###############################################################
#  Generated by:      Cadence Innovus 22.16-s082_1
#  OS:                Linux x86_64(Host ID localhost.localdomain)
#  Generated on:      Sat Aug  8 01:09:43 2026
#  Design:            CNN_1D_Core_USE_ASIC_SRAM1
#  Command:           write_lef_abstract -extractBlockObs -cutObsMinSpacing -specifyTopLayer metal10 -5.8 -extractBlockPGPinLayers {metal9 metal10} /home/hients/my_design/CNN_300_cp3/output/06_route_opt/CNN_1D_Core_USE_ASIC_SRAM1.lef
###############################################################

VERSION 5.8 ;

BUSBITCHARS "[]" ;
DIVIDERCHAR "/" ;

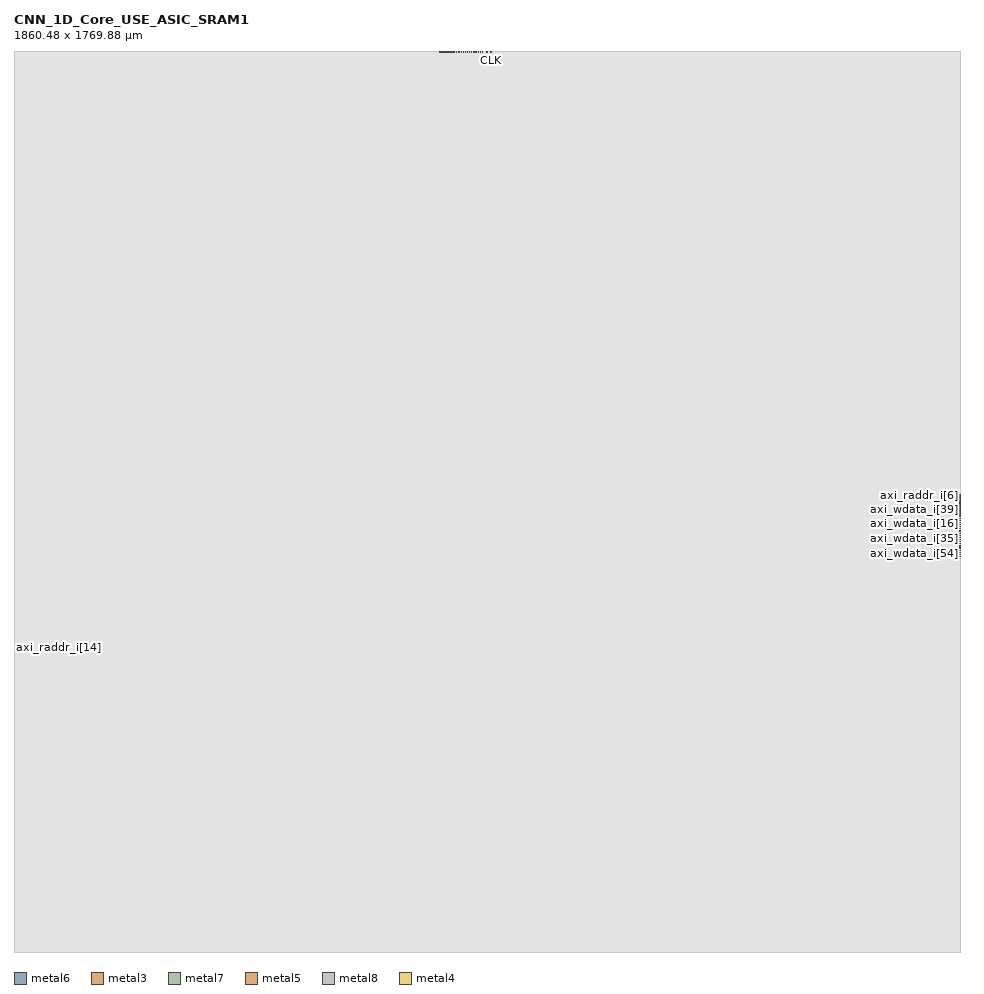
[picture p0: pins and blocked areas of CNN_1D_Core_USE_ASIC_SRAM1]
MACRO CNN_1D_Core_USE_ASIC_SRAM1
  CLASS BLOCK ;
  SIZE 1860.480000 BY 1769.880000 ;
  FOREIGN CNN_1D_Core_USE_ASIC_SRAM1 0.000000 0.000000 ;
  ORIGIN 0 0 ;
  SYMMETRY X Y R90 ;
  PIN CLK
    DIRECTION INPUT ;
    USE SIGNAL ;
    PORT
      LAYER metal6 ;
        RECT 937.990000 1769.740000 938.130000 1769.880000 ;
    END
  END CLK
  PIN RST
    DIRECTION INPUT ;
    USE SIGNAL ;
    PORT
      LAYER metal6 ;
        RECT 930.150000 1769.740000 930.290000 1769.880000 ;
    END
  END RST
  PIN axi_waddr_i[14]
    DIRECTION INPUT ;
    USE SIGNAL ;
    PORT
      LAYER metal3 ;
        RECT 1860.410000 896.245000 1860.480000 896.315000 ;
    END
  END axi_waddr_i[14]
  PIN axi_waddr_i[13]
    DIRECTION INPUT ;
    USE SIGNAL ;
    PORT
      LAYER metal7 ;
        RECT 1860.080000 882.360000 1860.480000 882.760000 ;
    END
  END axi_waddr_i[13]
  PIN axi_waddr_i[12]
    DIRECTION INPUT ;
    USE SIGNAL ;
    PORT
      LAYER metal5 ;
        RECT 1860.340000 893.970000 1860.480000 894.110000 ;
    END
  END axi_waddr_i[12]
  PIN axi_waddr_i[11]
    DIRECTION INPUT ;
    USE SIGNAL ;
    PORT
      LAYER metal3 ;
        RECT 1860.410000 896.945000 1860.480000 897.015000 ;
    END
  END axi_waddr_i[11]
  PIN axi_waddr_i[10]
    DIRECTION INPUT ;
    USE SIGNAL ;
    PORT
      LAYER metal7 ;
        RECT 1860.080000 886.560000 1860.480000 886.960000 ;
    END
  END axi_waddr_i[10]
  PIN axi_waddr_i[9]
    DIRECTION INPUT ;
    USE SIGNAL ;
    PORT
      LAYER metal3 ;
        RECT 1860.410000 894.145000 1860.480000 894.215000 ;
    END
  END axi_waddr_i[9]
  PIN axi_waddr_i[8]
    DIRECTION INPUT ;
    USE SIGNAL ;
    PORT
      LAYER metal7 ;
        RECT 1860.080000 869.760000 1860.480000 870.160000 ;
    END
  END axi_waddr_i[8]
  PIN axi_waddr_i[7]
    DIRECTION INPUT ;
    USE SIGNAL ;
    PORT
      LAYER metal5 ;
        RECT 1860.340000 889.770000 1860.480000 889.910000 ;
    END
  END axi_waddr_i[7]
  PIN axi_waddr_i[6]
    DIRECTION INPUT ;
    USE SIGNAL ;
    PORT
      LAYER metal3 ;
        RECT 1860.410000 894.845000 1860.480000 894.915000 ;
    END
  END axi_waddr_i[6]
  PIN axi_waddr_i[5]
    DIRECTION INPUT ;
    USE SIGNAL ;
    PORT
      LAYER metal7 ;
        RECT 1860.080000 873.960000 1860.480000 874.360000 ;
    END
  END axi_waddr_i[5]
  PIN axi_waddr_i[4]
    DIRECTION INPUT ;
    USE SIGNAL ;
    PORT
      LAYER metal5 ;
        RECT 1860.340000 891.170000 1860.480000 891.310000 ;
    END
  END axi_waddr_i[4]
  PIN axi_waddr_i[3]
    DIRECTION INPUT ;
    USE SIGNAL ;
    PORT
      LAYER metal3 ;
        RECT 1860.410000 895.545000 1860.480000 895.615000 ;
    END
  END axi_waddr_i[3]
  PIN axi_waddr_i[2]
    DIRECTION INPUT ;
    USE SIGNAL ;
    PORT
      LAYER metal7 ;
        RECT 1860.080000 878.160000 1860.480000 878.560000 ;
    END
  END axi_waddr_i[2]
  PIN axi_waddr_i[1]
    DIRECTION INPUT ;
    USE SIGNAL ;
    PORT
      LAYER metal5 ;
        RECT 1860.340000 892.570000 1860.480000 892.710000 ;
    END
  END axi_waddr_i[1]
  PIN axi_waddr_i[0]
    DIRECTION INPUT ;
    USE SIGNAL ;
    PORT
      LAYER metal5 ;
        RECT 1860.340000 895.370000 1860.480000 895.510000 ;
    END
  END axi_waddr_i[0]
  PIN axi_wdata_i[63]
    DIRECTION INPUT ;
    USE SIGNAL ;
    PORT
      LAYER metal3 ;
        RECT 1860.410000 880.145000 1860.480000 880.215000 ;
    END
  END axi_wdata_i[63]
  PIN axi_wdata_i[62]
    DIRECTION INPUT ;
    USE SIGNAL ;
    PORT
      LAYER metal7 ;
        RECT 1860.080000 785.760000 1860.480000 786.160000 ;
    END
  END axi_wdata_i[62]
  PIN axi_wdata_i[61]
    DIRECTION INPUT ;
    USE SIGNAL ;
    PORT
      LAYER metal5 ;
        RECT 1860.340000 861.770000 1860.480000 861.910000 ;
    END
  END axi_wdata_i[61]
  PIN axi_wdata_i[60]
    DIRECTION INPUT ;
    USE SIGNAL ;
    PORT
      LAYER metal3 ;
        RECT 1860.410000 880.845000 1860.480000 880.915000 ;
    END
  END axi_wdata_i[60]
  PIN axi_wdata_i[59]
    DIRECTION INPUT ;
    USE SIGNAL ;
    PORT
      LAYER metal5 ;
        RECT 1860.340000 863.170000 1860.480000 863.310000 ;
    END
  END axi_wdata_i[59]
  PIN axi_wdata_i[58]
    DIRECTION INPUT ;
    USE SIGNAL ;
    PORT
      LAYER metal3 ;
        RECT 1860.410000 881.545000 1860.480000 881.615000 ;
    END
  END axi_wdata_i[58]
  PIN axi_wdata_i[57]
    DIRECTION INPUT ;
    USE SIGNAL ;
    PORT
      LAYER metal7 ;
        RECT 1860.080000 794.160000 1860.480000 794.560000 ;
    END
  END axi_wdata_i[57]
  PIN axi_wdata_i[56]
    DIRECTION INPUT ;
    USE SIGNAL ;
    PORT
      LAYER metal5 ;
        RECT 1860.340000 864.570000 1860.480000 864.710000 ;
    END
  END axi_wdata_i[56]
  PIN axi_wdata_i[55]
    DIRECTION INPUT ;
    USE SIGNAL ;
    PORT
      LAYER metal3 ;
        RECT 1860.410000 882.245000 1860.480000 882.315000 ;
    END
  END axi_wdata_i[55]
  PIN axi_wdata_i[54]
    DIRECTION INPUT ;
    USE SIGNAL ;
    PORT
      LAYER metal7 ;
        RECT 1860.080000 798.360000 1860.480000 798.760000 ;
    END
  END axi_wdata_i[54]
  PIN axi_wdata_i[53]
    DIRECTION INPUT ;
    USE SIGNAL ;
    PORT
      LAYER metal5 ;
        RECT 1860.340000 865.970000 1860.480000 866.110000 ;
    END
  END axi_wdata_i[53]
  PIN axi_wdata_i[52]
    DIRECTION INPUT ;
    USE SIGNAL ;
    PORT
      LAYER metal3 ;
        RECT 1860.410000 882.945000 1860.480000 883.015000 ;
    END
  END axi_wdata_i[52]
  PIN axi_wdata_i[51]
    DIRECTION INPUT ;
    USE SIGNAL ;
    PORT
      LAYER metal7 ;
        RECT 1860.080000 802.560000 1860.480000 802.960000 ;
    END
  END axi_wdata_i[51]
  PIN axi_wdata_i[50]
    DIRECTION INPUT ;
    USE SIGNAL ;
    PORT
      LAYER metal5 ;
        RECT 1860.340000 867.370000 1860.480000 867.510000 ;
    END
  END axi_wdata_i[50]
  PIN axi_wdata_i[49]
    DIRECTION INPUT ;
    USE SIGNAL ;
    PORT
      LAYER metal7 ;
        RECT 1860.080000 806.760000 1860.480000 807.160000 ;
    END
  END axi_wdata_i[49]
  PIN axi_wdata_i[48]
    DIRECTION INPUT ;
    USE SIGNAL ;
    PORT
      LAYER metal5 ;
        RECT 1860.340000 868.770000 1860.480000 868.910000 ;
    END
  END axi_wdata_i[48]
  PIN axi_wdata_i[47]
    DIRECTION INPUT ;
    USE SIGNAL ;
    PORT
      LAYER metal3 ;
        RECT 1860.410000 884.345000 1860.480000 884.415000 ;
    END
  END axi_wdata_i[47]
  PIN axi_wdata_i[46]
    DIRECTION INPUT ;
    USE SIGNAL ;
    PORT
      LAYER metal7 ;
        RECT 1860.080000 810.960000 1860.480000 811.360000 ;
    END
  END axi_wdata_i[46]
  PIN axi_wdata_i[45]
    DIRECTION INPUT ;
    USE SIGNAL ;
    PORT
      LAYER metal5 ;
        RECT 1860.340000 870.170000 1860.480000 870.310000 ;
    END
  END axi_wdata_i[45]
  PIN axi_wdata_i[44]
    DIRECTION INPUT ;
    USE SIGNAL ;
    PORT
      LAYER metal3 ;
        RECT 1860.410000 885.045000 1860.480000 885.115000 ;
    END
  END axi_wdata_i[44]
  PIN axi_wdata_i[43]
    DIRECTION INPUT ;
    USE SIGNAL ;
    PORT
      LAYER metal7 ;
        RECT 1860.080000 815.160000 1860.480000 815.560000 ;
    END
  END axi_wdata_i[43]
  PIN axi_wdata_i[42]
    DIRECTION INPUT ;
    USE SIGNAL ;
    PORT
      LAYER metal5 ;
        RECT 1860.340000 871.570000 1860.480000 871.710000 ;
    END
  END axi_wdata_i[42]
  PIN axi_wdata_i[41]
    DIRECTION INPUT ;
    USE SIGNAL ;
    PORT
      LAYER metal3 ;
        RECT 1860.410000 885.745000 1860.480000 885.815000 ;
    END
  END axi_wdata_i[41]
  PIN axi_wdata_i[40]
    DIRECTION INPUT ;
    USE SIGNAL ;
    PORT
      LAYER metal7 ;
        RECT 1860.080000 819.360000 1860.480000 819.760000 ;
    END
  END axi_wdata_i[40]
  PIN axi_wdata_i[39]
    DIRECTION INPUT ;
    USE SIGNAL ;
    PORT
      LAYER metal3 ;
        RECT 1860.410000 886.445000 1860.480000 886.515000 ;
    END
  END axi_wdata_i[39]
  PIN axi_wdata_i[38]
    DIRECTION INPUT ;
    USE SIGNAL ;
    PORT
      LAYER metal7 ;
        RECT 1860.080000 823.560000 1860.480000 823.960000 ;
    END
  END axi_wdata_i[38]
  PIN axi_wdata_i[37]
    DIRECTION INPUT ;
    USE SIGNAL ;
    PORT
      LAYER metal5 ;
        RECT 1860.340000 874.370000 1860.480000 874.510000 ;
    END
  END axi_wdata_i[37]
  PIN axi_wdata_i[36]
    DIRECTION INPUT ;
    USE SIGNAL ;
    PORT
      LAYER metal3 ;
        RECT 1860.410000 887.145000 1860.480000 887.215000 ;
    END
  END axi_wdata_i[36]
  PIN axi_wdata_i[35]
    DIRECTION INPUT ;
    USE SIGNAL ;
    PORT
      LAYER metal7 ;
        RECT 1860.080000 827.760000 1860.480000 828.160000 ;
    END
  END axi_wdata_i[35]
  PIN axi_wdata_i[34]
    DIRECTION INPUT ;
    USE SIGNAL ;
    PORT
      LAYER metal5 ;
        RECT 1860.340000 875.770000 1860.480000 875.910000 ;
    END
  END axi_wdata_i[34]
  PIN axi_wdata_i[33]
    DIRECTION INPUT ;
    USE SIGNAL ;
    PORT
      LAYER metal3 ;
        RECT 1860.410000 887.845000 1860.480000 887.915000 ;
    END
  END axi_wdata_i[33]
  PIN axi_wdata_i[32]
    DIRECTION INPUT ;
    USE SIGNAL ;
    PORT
      LAYER metal7 ;
        RECT 1860.080000 831.960000 1860.480000 832.360000 ;
    END
  END axi_wdata_i[32]
  PIN axi_wdata_i[31]
    DIRECTION INPUT ;
    USE SIGNAL ;
    PORT
      LAYER metal5 ;
        RECT 1860.340000 877.170000 1860.480000 877.310000 ;
    END
  END axi_wdata_i[31]
  PIN axi_wdata_i[30]
    DIRECTION INPUT ;
    USE SIGNAL ;
    PORT
      LAYER metal3 ;
        RECT 1860.410000 888.545000 1860.480000 888.615000 ;
    END
  END axi_wdata_i[30]
  PIN axi_wdata_i[29]
    DIRECTION INPUT ;
    USE SIGNAL ;
    PORT
      LAYER metal5 ;
        RECT 1860.340000 878.570000 1860.480000 878.710000 ;
    END
  END axi_wdata_i[29]
  PIN axi_wdata_i[28]
    DIRECTION INPUT ;
    USE SIGNAL ;
    PORT
      LAYER metal3 ;
        RECT 1860.410000 889.245000 1860.480000 889.315000 ;
    END
  END axi_wdata_i[28]
  PIN axi_wdata_i[27]
    DIRECTION INPUT ;
    USE SIGNAL ;
    PORT
      LAYER metal7 ;
        RECT 1860.080000 840.360000 1860.480000 840.760000 ;
    END
  END axi_wdata_i[27]
  PIN axi_wdata_i[26]
    DIRECTION INPUT ;
    USE SIGNAL ;
    PORT
      LAYER metal5 ;
        RECT 1860.340000 879.970000 1860.480000 880.110000 ;
    END
  END axi_wdata_i[26]
  PIN axi_wdata_i[25]
    DIRECTION INPUT ;
    USE SIGNAL ;
    PORT
      LAYER metal3 ;
        RECT 1860.410000 889.945000 1860.480000 890.015000 ;
    END
  END axi_wdata_i[25]
  PIN axi_wdata_i[24]
    DIRECTION INPUT ;
    USE SIGNAL ;
    PORT
      LAYER metal7 ;
        RECT 1860.080000 844.560000 1860.480000 844.960000 ;
    END
  END axi_wdata_i[24]
  PIN axi_wdata_i[23]
    DIRECTION INPUT ;
    USE SIGNAL ;
    PORT
      LAYER metal5 ;
        RECT 1860.340000 881.370000 1860.480000 881.510000 ;
    END
  END axi_wdata_i[23]
  PIN axi_wdata_i[22]
    DIRECTION INPUT ;
    USE SIGNAL ;
    PORT
      LAYER metal3 ;
        RECT 1860.410000 890.645000 1860.480000 890.715000 ;
    END
  END axi_wdata_i[22]
  PIN axi_wdata_i[21]
    DIRECTION INPUT ;
    USE SIGNAL ;
    PORT
      LAYER metal7 ;
        RECT 1860.080000 848.760000 1860.480000 849.160000 ;
    END
  END axi_wdata_i[21]
  PIN axi_wdata_i[20]
    DIRECTION INPUT ;
    USE SIGNAL ;
    PORT
      LAYER metal5 ;
        RECT 1860.340000 882.770000 1860.480000 882.910000 ;
    END
  END axi_wdata_i[20]
  PIN axi_wdata_i[19]
    DIRECTION INPUT ;
    USE SIGNAL ;
    PORT
      LAYER metal7 ;
        RECT 1860.080000 852.960000 1860.480000 853.360000 ;
    END
  END axi_wdata_i[19]
  PIN axi_wdata_i[18]
    DIRECTION INPUT ;
    USE SIGNAL ;
    PORT
      LAYER metal5 ;
        RECT 1860.340000 884.170000 1860.480000 884.310000 ;
    END
  END axi_wdata_i[18]
  PIN axi_wdata_i[17]
    DIRECTION INPUT ;
    USE SIGNAL ;
    PORT
      LAYER metal3 ;
        RECT 1860.410000 892.045000 1860.480000 892.115000 ;
    END
  END axi_wdata_i[17]
  PIN axi_wdata_i[16]
    DIRECTION INPUT ;
    USE SIGNAL ;
    PORT
      LAYER metal7 ;
        RECT 1860.080000 857.160000 1860.480000 857.560000 ;
    END
  END axi_wdata_i[16]
  PIN axi_wdata_i[15]
    DIRECTION INPUT ;
    USE SIGNAL ;
    PORT
      LAYER metal5 ;
        RECT 1860.340000 885.570000 1860.480000 885.710000 ;
    END
  END axi_wdata_i[15]
  PIN axi_wdata_i[14]
    DIRECTION INPUT ;
    USE SIGNAL ;
    PORT
      LAYER metal3 ;
        RECT 1860.410000 892.745000 1860.480000 892.815000 ;
    END
  END axi_wdata_i[14]
  PIN axi_wdata_i[13]
    DIRECTION INPUT ;
    USE SIGNAL ;
    PORT
      LAYER metal7 ;
        RECT 1860.080000 861.360000 1860.480000 861.760000 ;
    END
  END axi_wdata_i[13]
  PIN axi_wdata_i[12]
    DIRECTION INPUT ;
    USE SIGNAL ;
    PORT
      LAYER metal5 ;
        RECT 1860.340000 886.970000 1860.480000 887.110000 ;
    END
  END axi_wdata_i[12]
  PIN axi_wdata_i[11]
    DIRECTION INPUT ;
    USE SIGNAL ;
    PORT
      LAYER metal3 ;
        RECT 1860.410000 893.445000 1860.480000 893.515000 ;
    END
  END axi_wdata_i[11]
  PIN axi_wdata_i[10]
    DIRECTION INPUT ;
    USE SIGNAL ;
    PORT
      LAYER metal7 ;
        RECT 1860.080000 865.560000 1860.480000 865.960000 ;
    END
  END axi_wdata_i[10]
  PIN axi_wdata_i[9]
    DIRECTION INPUT ;
    USE SIGNAL ;
    PORT
      LAYER metal5 ;
        RECT 1860.340000 858.970000 1860.480000 859.110000 ;
    END
  END axi_wdata_i[9]
  PIN axi_wdata_i[8]
    DIRECTION INPUT ;
    USE SIGNAL ;
    PORT
      LAYER metal3 ;
        RECT 1860.410000 879.445000 1860.480000 879.515000 ;
    END
  END axi_wdata_i[8]
  PIN axi_wdata_i[7]
    DIRECTION INPUT ;
    USE SIGNAL ;
    PORT
      LAYER metal7 ;
        RECT 1860.080000 781.560000 1860.480000 781.960000 ;
    END
  END axi_wdata_i[7]
  PIN axi_wdata_i[6]
    DIRECTION INPUT ;
    USE SIGNAL ;
    PORT
      LAYER metal5 ;
        RECT 1860.340000 860.370000 1860.480000 860.510000 ;
    END
  END axi_wdata_i[6]
  PIN axi_wdata_i[5]
    DIRECTION INPUT ;
    USE SIGNAL ;
    PORT
      LAYER metal7 ;
        RECT 1860.080000 789.960000 1860.480000 790.360000 ;
    END
  END axi_wdata_i[5]
  PIN axi_wdata_i[4]
    DIRECTION INPUT ;
    USE SIGNAL ;
    PORT
      LAYER metal3 ;
        RECT 1860.410000 883.645000 1860.480000 883.715000 ;
    END
  END axi_wdata_i[4]
  PIN axi_wdata_i[3]
    DIRECTION INPUT ;
    USE SIGNAL ;
    PORT
      LAYER metal5 ;
        RECT 1860.340000 872.970000 1860.480000 873.110000 ;
    END
  END axi_wdata_i[3]
  PIN axi_wdata_i[2]
    DIRECTION INPUT ;
    USE SIGNAL ;
    PORT
      LAYER metal7 ;
        RECT 1860.080000 836.160000 1860.480000 836.560000 ;
    END
  END axi_wdata_i[2]
  PIN axi_wdata_i[1]
    DIRECTION INPUT ;
    USE SIGNAL ;
    PORT
      LAYER metal3 ;
        RECT 1860.410000 891.345000 1860.480000 891.415000 ;
    END
  END axi_wdata_i[1]
  PIN axi_wdata_i[0]
    DIRECTION INPUT ;
    USE SIGNAL ;
    PORT
      LAYER metal5 ;
        RECT 1860.340000 888.370000 1860.480000 888.510000 ;
    END
  END axi_wdata_i[0]
  PIN axi_wvalid_i
    DIRECTION INPUT ;
    USE SIGNAL ;
    PORT
      LAYER metal7 ;
        RECT 1860.080000 777.360000 1860.480000 777.760000 ;
    END
  END axi_wvalid_i
  PIN axi_raddr_i[14]
    DIRECTION INPUT ;
    USE SIGNAL ;
    PORT
      LAYER metal3 ;
        RECT 0.000000 598.885000 0.070000 598.955000 ;
    END
  END axi_raddr_i[14]
  PIN axi_raddr_i[13]
    DIRECTION INPUT ;
    USE SIGNAL ;
    PORT
      LAYER metal5 ;
        RECT 0.000000 599.130000 0.140000 599.270000 ;
    END
  END axi_raddr_i[13]
  PIN axi_raddr_i[12]
    DIRECTION INPUT ;
    USE SIGNAL ;
    PORT
      LAYER metal7 ;
        RECT 0.000000 600.120000 0.400000 600.520000 ;
    END
  END axi_raddr_i[12]
  PIN axi_raddr_i[11]
    DIRECTION INPUT ;
    USE SIGNAL ;
    PORT
      LAYER metal5 ;
        RECT 1860.340000 899.570000 1860.480000 899.710000 ;
    END
  END axi_raddr_i[11]
  PIN axi_raddr_i[10]
    DIRECTION INPUT ;
    USE SIGNAL ;
    PORT
      LAYER metal3 ;
        RECT 1860.410000 899.745000 1860.480000 899.815000 ;
    END
  END axi_raddr_i[10]
  PIN axi_raddr_i[9]
    DIRECTION INPUT ;
    USE SIGNAL ;
    PORT
      LAYER metal3 ;
        RECT 1860.410000 897.645000 1860.480000 897.715000 ;
    END
  END axi_raddr_i[9]
  PIN axi_raddr_i[8]
    DIRECTION INPUT ;
    USE SIGNAL ;
    PORT
      LAYER metal7 ;
        RECT 1860.080000 890.760000 1860.480000 891.160000 ;
    END
  END axi_raddr_i[8]
  PIN axi_raddr_i[7]
    DIRECTION INPUT ;
    USE SIGNAL ;
    PORT
      LAYER metal5 ;
        RECT 1860.340000 896.770000 1860.480000 896.910000 ;
    END
  END axi_raddr_i[7]
  PIN axi_raddr_i[6]
    DIRECTION INPUT ;
    USE SIGNAL ;
    PORT
      LAYER metal3 ;
        RECT 1860.410000 898.345000 1860.480000 898.415000 ;
    END
  END axi_raddr_i[6]
  PIN axi_raddr_i[5]
    DIRECTION INPUT ;
    USE SIGNAL ;
    PORT
      LAYER metal7 ;
        RECT 1860.080000 894.960000 1860.480000 895.360000 ;
    END
  END axi_raddr_i[5]
  PIN axi_raddr_i[4]
    DIRECTION INPUT ;
    USE SIGNAL ;
    PORT
      LAYER metal5 ;
        RECT 1860.340000 898.170000 1860.480000 898.310000 ;
    END
  END axi_raddr_i[4]
  PIN axi_raddr_i[3]
    DIRECTION INPUT ;
    USE SIGNAL ;
    PORT
      LAYER metal3 ;
        RECT 1860.410000 899.045000 1860.480000 899.115000 ;
    END
  END axi_raddr_i[3]
  PIN axi_raddr_i[2]
    DIRECTION INPUT ;
    USE SIGNAL ;
    PORT
      LAYER metal7 ;
        RECT 1860.080000 899.160000 1860.480000 899.560000 ;
    END
  END axi_raddr_i[2]
  PIN axi_raddr_i[1]
    DIRECTION INPUT ;
    USE SIGNAL ;
    PORT
      LAYER metal3 ;
        RECT 0.000000 600.005000 0.070000 600.075000 ;
    END
  END axi_raddr_i[1]
  PIN axi_raddr_i[0]
    DIRECTION INPUT ;
    USE SIGNAL ;
    PORT
      LAYER metal5 ;
        RECT 0.000000 600.810000 0.140000 600.950000 ;
    END
  END axi_raddr_i[0]
  PIN axi_arvalid_i
    DIRECTION INPUT ;
    USE SIGNAL ;
    PORT
      LAYER metal7 ;
        RECT 0.000000 604.320000 0.400000 604.720000 ;
    END
  END axi_arvalid_i
  PIN axi_rdata_o[63]
    DIRECTION OUTPUT ;
    USE SIGNAL ;
    PORT
      LAYER metal8 ;
        RECT 916.860000 1769.480000 917.260000 1769.880000 ;
    END
  END axi_rdata_o[63]
  PIN axi_rdata_o[62]
    DIRECTION OUTPUT ;
    USE SIGNAL ;
    PORT
      LAYER metal6 ;
        RECT 862.950000 1769.740000 863.090000 1769.880000 ;
    END
  END axi_rdata_o[62]
  PIN axi_rdata_o[61]
    DIRECTION OUTPUT ;
    USE SIGNAL ;
    PORT
      LAYER metal4 ;
        RECT 862.950000 1769.740000 863.090000 1769.880000 ;
    END
  END axi_rdata_o[61]
  PIN axi_rdata_o[60]
    DIRECTION OUTPUT ;
    USE SIGNAL ;
    PORT
      LAYER metal8 ;
        RECT 912.660000 1769.480000 913.060000 1769.880000 ;
    END
  END axi_rdata_o[60]
  PIN axi_rdata_o[59]
    DIRECTION OUTPUT ;
    USE SIGNAL ;
    PORT
      LAYER metal4 ;
        RECT 861.550000 1769.740000 861.690000 1769.880000 ;
    END
  END axi_rdata_o[59]
  PIN axi_rdata_o[58]
    DIRECTION OUTPUT ;
    USE SIGNAL ;
    PORT
      LAYER metal8 ;
        RECT 908.460000 1769.480000 908.860000 1769.880000 ;
    END
  END axi_rdata_o[58]
  PIN axi_rdata_o[57]
    DIRECTION OUTPUT ;
    USE SIGNAL ;
    PORT
      LAYER metal6 ;
        RECT 860.150000 1769.740000 860.290000 1769.880000 ;
    END
  END axi_rdata_o[57]
  PIN axi_rdata_o[56]
    DIRECTION OUTPUT ;
    USE SIGNAL ;
    PORT
      LAYER metal4 ;
        RECT 860.150000 1769.740000 860.290000 1769.880000 ;
    END
  END axi_rdata_o[56]
  PIN axi_rdata_o[55]
    DIRECTION OUTPUT ;
    USE SIGNAL ;
    PORT
      LAYER metal8 ;
        RECT 904.260000 1769.480000 904.660000 1769.880000 ;
    END
  END axi_rdata_o[55]
  PIN axi_rdata_o[54]
    DIRECTION OUTPUT ;
    USE SIGNAL ;
    PORT
      LAYER metal6 ;
        RECT 858.750000 1769.740000 858.890000 1769.880000 ;
    END
  END axi_rdata_o[54]
  PIN axi_rdata_o[53]
    DIRECTION OUTPUT ;
    USE SIGNAL ;
    PORT
      LAYER metal4 ;
        RECT 858.750000 1769.740000 858.890000 1769.880000 ;
    END
  END axi_rdata_o[53]
  PIN axi_rdata_o[52]
    DIRECTION OUTPUT ;
    USE SIGNAL ;
    PORT
      LAYER metal8 ;
        RECT 900.060000 1769.480000 900.460000 1769.880000 ;
    END
  END axi_rdata_o[52]
  PIN axi_rdata_o[51]
    DIRECTION OUTPUT ;
    USE SIGNAL ;
    PORT
      LAYER metal6 ;
        RECT 857.350000 1769.740000 857.490000 1769.880000 ;
    END
  END axi_rdata_o[51]
  PIN axi_rdata_o[50]
    DIRECTION OUTPUT ;
    USE SIGNAL ;
    PORT
      LAYER metal4 ;
        RECT 857.350000 1769.740000 857.490000 1769.880000 ;
    END
  END axi_rdata_o[50]
  PIN axi_rdata_o[49]
    DIRECTION OUTPUT ;
    USE SIGNAL ;
    PORT
      LAYER metal6 ;
        RECT 855.950000 1769.740000 856.090000 1769.880000 ;
    END
  END axi_rdata_o[49]
  PIN axi_rdata_o[48]
    DIRECTION OUTPUT ;
    USE SIGNAL ;
    PORT
      LAYER metal4 ;
        RECT 855.950000 1769.740000 856.090000 1769.880000 ;
    END
  END axi_rdata_o[48]
  PIN axi_rdata_o[47]
    DIRECTION OUTPUT ;
    USE SIGNAL ;
    PORT
      LAYER metal8 ;
        RECT 891.660000 1769.480000 892.060000 1769.880000 ;
    END
  END axi_rdata_o[47]
  PIN axi_rdata_o[46]
    DIRECTION OUTPUT ;
    USE SIGNAL ;
    PORT
      LAYER metal6 ;
        RECT 854.550000 1769.740000 854.690000 1769.880000 ;
    END
  END axi_rdata_o[46]
  PIN axi_rdata_o[45]
    DIRECTION OUTPUT ;
    USE SIGNAL ;
    PORT
      LAYER metal4 ;
        RECT 854.550000 1769.740000 854.690000 1769.880000 ;
    END
  END axi_rdata_o[45]
  PIN axi_rdata_o[44]
    DIRECTION OUTPUT ;
    USE SIGNAL ;
    PORT
      LAYER metal8 ;
        RECT 887.460000 1769.480000 887.860000 1769.880000 ;
    END
  END axi_rdata_o[44]
  PIN axi_rdata_o[43]
    DIRECTION OUTPUT ;
    USE SIGNAL ;
    PORT
      LAYER metal6 ;
        RECT 853.150000 1769.740000 853.290000 1769.880000 ;
    END
  END axi_rdata_o[43]
  PIN axi_rdata_o[42]
    DIRECTION OUTPUT ;
    USE SIGNAL ;
    PORT
      LAYER metal4 ;
        RECT 853.150000 1769.740000 853.290000 1769.880000 ;
    END
  END axi_rdata_o[42]
  PIN axi_rdata_o[41]
    DIRECTION OUTPUT ;
    USE SIGNAL ;
    PORT
      LAYER metal8 ;
        RECT 883.260000 1769.480000 883.660000 1769.880000 ;
    END
  END axi_rdata_o[41]
  PIN axi_rdata_o[40]
    DIRECTION OUTPUT ;
    USE SIGNAL ;
    PORT
      LAYER metal6 ;
        RECT 851.750000 1769.740000 851.890000 1769.880000 ;
    END
  END axi_rdata_o[40]
  PIN axi_rdata_o[39]
    DIRECTION OUTPUT ;
    USE SIGNAL ;
    PORT
      LAYER metal8 ;
        RECT 879.060000 1769.480000 879.460000 1769.880000 ;
    END
  END axi_rdata_o[39]
  PIN axi_rdata_o[38]
    DIRECTION OUTPUT ;
    USE SIGNAL ;
    PORT
      LAYER metal6 ;
        RECT 850.350000 1769.740000 850.490000 1769.880000 ;
    END
  END axi_rdata_o[38]
  PIN axi_rdata_o[37]
    DIRECTION OUTPUT ;
    USE SIGNAL ;
    PORT
      LAYER metal4 ;
        RECT 850.350000 1769.740000 850.490000 1769.880000 ;
    END
  END axi_rdata_o[37]
  PIN axi_rdata_o[36]
    DIRECTION OUTPUT ;
    USE SIGNAL ;
    PORT
      LAYER metal8 ;
        RECT 874.860000 1769.480000 875.260000 1769.880000 ;
    END
  END axi_rdata_o[36]
  PIN axi_rdata_o[35]
    DIRECTION OUTPUT ;
    USE SIGNAL ;
    PORT
      LAYER metal6 ;
        RECT 848.950000 1769.740000 849.090000 1769.880000 ;
    END
  END axi_rdata_o[35]
  PIN axi_rdata_o[34]
    DIRECTION OUTPUT ;
    USE SIGNAL ;
    PORT
      LAYER metal4 ;
        RECT 848.950000 1769.740000 849.090000 1769.880000 ;
    END
  END axi_rdata_o[34]
  PIN axi_rdata_o[33]
    DIRECTION OUTPUT ;
    USE SIGNAL ;
    PORT
      LAYER metal8 ;
        RECT 870.660000 1769.480000 871.060000 1769.880000 ;
    END
  END axi_rdata_o[33]
  PIN axi_rdata_o[32]
    DIRECTION OUTPUT ;
    USE SIGNAL ;
    PORT
      LAYER metal6 ;
        RECT 847.550000 1769.740000 847.690000 1769.880000 ;
    END
  END axi_rdata_o[32]
  PIN axi_rdata_o[31]
    DIRECTION OUTPUT ;
    USE SIGNAL ;
    PORT
      LAYER metal4 ;
        RECT 847.550000 1769.740000 847.690000 1769.880000 ;
    END
  END axi_rdata_o[31]
  PIN axi_rdata_o[30]
    DIRECTION OUTPUT ;
    USE SIGNAL ;
    PORT
      LAYER metal8 ;
        RECT 866.460000 1769.480000 866.860000 1769.880000 ;
    END
  END axi_rdata_o[30]
  PIN axi_rdata_o[29]
    DIRECTION OUTPUT ;
    USE SIGNAL ;
    PORT
      LAYER metal4 ;
        RECT 846.150000 1769.740000 846.290000 1769.880000 ;
    END
  END axi_rdata_o[29]
  PIN axi_rdata_o[28]
    DIRECTION OUTPUT ;
    USE SIGNAL ;
    PORT
      LAYER metal8 ;
        RECT 862.260000 1769.480000 862.660000 1769.880000 ;
    END
  END axi_rdata_o[28]
  PIN axi_rdata_o[27]
    DIRECTION OUTPUT ;
    USE SIGNAL ;
    PORT
      LAYER metal6 ;
        RECT 844.750000 1769.740000 844.890000 1769.880000 ;
    END
  END axi_rdata_o[27]
  PIN axi_rdata_o[26]
    DIRECTION OUTPUT ;
    USE SIGNAL ;
    PORT
      LAYER metal4 ;
        RECT 844.750000 1769.740000 844.890000 1769.880000 ;
    END
  END axi_rdata_o[26]
  PIN axi_rdata_o[25]
    DIRECTION OUTPUT ;
    USE SIGNAL ;
    PORT
      LAYER metal8 ;
        RECT 858.060000 1769.480000 858.460000 1769.880000 ;
    END
  END axi_rdata_o[25]
  PIN axi_rdata_o[24]
    DIRECTION OUTPUT ;
    USE SIGNAL ;
    PORT
      LAYER metal6 ;
        RECT 843.350000 1769.740000 843.490000 1769.880000 ;
    END
  END axi_rdata_o[24]
  PIN axi_rdata_o[23]
    DIRECTION OUTPUT ;
    USE SIGNAL ;
    PORT
      LAYER metal4 ;
        RECT 843.350000 1769.740000 843.490000 1769.880000 ;
    END
  END axi_rdata_o[23]
  PIN axi_rdata_o[22]
    DIRECTION OUTPUT ;
    USE SIGNAL ;
    PORT
      LAYER metal8 ;
        RECT 853.860000 1769.480000 854.260000 1769.880000 ;
    END
  END axi_rdata_o[22]
  PIN axi_rdata_o[21]
    DIRECTION OUTPUT ;
    USE SIGNAL ;
    PORT
      LAYER metal6 ;
        RECT 841.950000 1769.740000 842.090000 1769.880000 ;
    END
  END axi_rdata_o[21]
  PIN axi_rdata_o[20]
    DIRECTION OUTPUT ;
    USE SIGNAL ;
    PORT
      LAYER metal4 ;
        RECT 841.950000 1769.740000 842.090000 1769.880000 ;
    END
  END axi_rdata_o[20]
  PIN axi_rdata_o[19]
    DIRECTION OUTPUT ;
    USE SIGNAL ;
    PORT
      LAYER metal6 ;
        RECT 840.550000 1769.740000 840.690000 1769.880000 ;
    END
  END axi_rdata_o[19]
  PIN axi_rdata_o[18]
    DIRECTION OUTPUT ;
    USE SIGNAL ;
    PORT
      LAYER metal4 ;
        RECT 840.550000 1769.740000 840.690000 1769.880000 ;
    END
  END axi_rdata_o[18]
  PIN axi_rdata_o[17]
    DIRECTION OUTPUT ;
    USE SIGNAL ;
    PORT
      LAYER metal8 ;
        RECT 845.460000 1769.480000 845.860000 1769.880000 ;
    END
  END axi_rdata_o[17]
  PIN axi_rdata_o[16]
    DIRECTION OUTPUT ;
    USE SIGNAL ;
    PORT
      LAYER metal6 ;
        RECT 839.150000 1769.740000 839.290000 1769.880000 ;
    END
  END axi_rdata_o[16]
  PIN axi_rdata_o[15]
    DIRECTION OUTPUT ;
    USE SIGNAL ;
    PORT
      LAYER metal4 ;
        RECT 839.150000 1769.740000 839.290000 1769.880000 ;
    END
  END axi_rdata_o[15]
  PIN axi_rdata_o[14]
    DIRECTION OUTPUT ;
    USE SIGNAL ;
    PORT
      LAYER metal8 ;
        RECT 841.260000 1769.480000 841.660000 1769.880000 ;
    END
  END axi_rdata_o[14]
  PIN axi_rdata_o[13]
    DIRECTION OUTPUT ;
    USE SIGNAL ;
    PORT
      LAYER metal6 ;
        RECT 837.750000 1769.740000 837.890000 1769.880000 ;
    END
  END axi_rdata_o[13]
  PIN axi_rdata_o[12]
    DIRECTION OUTPUT ;
    USE SIGNAL ;
    PORT
      LAYER metal4 ;
        RECT 837.750000 1769.740000 837.890000 1769.880000 ;
    END
  END axi_rdata_o[12]
  PIN axi_rdata_o[11]
    DIRECTION OUTPUT ;
    USE SIGNAL ;
    PORT
      LAYER metal8 ;
        RECT 837.060000 1769.480000 837.460000 1769.880000 ;
    END
  END axi_rdata_o[11]
  PIN axi_rdata_o[10]
    DIRECTION OUTPUT ;
    USE SIGNAL ;
    PORT
      LAYER metal6 ;
        RECT 836.350000 1769.740000 836.490000 1769.880000 ;
    END
  END axi_rdata_o[10]
  PIN axi_rdata_o[9]
    DIRECTION OUTPUT ;
    USE SIGNAL ;
    PORT
      LAYER metal4 ;
        RECT 865.750000 1769.740000 865.890000 1769.880000 ;
    END
  END axi_rdata_o[9]
  PIN axi_rdata_o[8]
    DIRECTION OUTPUT ;
    USE SIGNAL ;
    PORT
      LAYER metal8 ;
        RECT 921.060000 1769.480000 921.460000 1769.880000 ;
    END
  END axi_rdata_o[8]
  PIN axi_rdata_o[7]
    DIRECTION OUTPUT ;
    USE SIGNAL ;
    PORT
      LAYER metal6 ;
        RECT 864.350000 1769.740000 864.490000 1769.880000 ;
    END
  END axi_rdata_o[7]
  PIN axi_rdata_o[6]
    DIRECTION OUTPUT ;
    USE SIGNAL ;
    PORT
      LAYER metal4 ;
        RECT 864.350000 1769.740000 864.490000 1769.880000 ;
    END
  END axi_rdata_o[6]
  PIN axi_rdata_o[5]
    DIRECTION OUTPUT ;
    USE SIGNAL ;
    PORT
      LAYER metal6 ;
        RECT 861.550000 1769.740000 861.690000 1769.880000 ;
    END
  END axi_rdata_o[5]
  PIN axi_rdata_o[4]
    DIRECTION OUTPUT ;
    USE SIGNAL ;
    PORT
      LAYER metal8 ;
        RECT 895.860000 1769.480000 896.260000 1769.880000 ;
    END
  END axi_rdata_o[4]
  PIN axi_rdata_o[3]
    DIRECTION OUTPUT ;
    USE SIGNAL ;
    PORT
      LAYER metal4 ;
        RECT 851.750000 1769.740000 851.890000 1769.880000 ;
    END
  END axi_rdata_o[3]
  PIN axi_rdata_o[2]
    DIRECTION OUTPUT ;
    USE SIGNAL ;
    PORT
      LAYER metal6 ;
        RECT 846.150000 1769.740000 846.290000 1769.880000 ;
    END
  END axi_rdata_o[2]
  PIN axi_rdata_o[1]
    DIRECTION OUTPUT ;
    USE SIGNAL ;
    PORT
      LAYER metal8 ;
        RECT 849.660000 1769.480000 850.060000 1769.880000 ;
    END
  END axi_rdata_o[1]
  PIN axi_rdata_o[0]
    DIRECTION OUTPUT ;
    USE SIGNAL ;
    PORT
      LAYER metal4 ;
        RECT 836.350000 1769.740000 836.490000 1769.880000 ;
    END
  END axi_rdata_o[0]
  OBS
    LAYER metal1 ;
      RECT 0.000000 0.000000 1860.480000 1769.880000 ;
    LAYER metal2 ;
      RECT 0.000000 0.000000 1860.480000 1769.880000 ;
    LAYER metal3 ;
      RECT 0.000000 899.885000 1860.480000 1769.880000 ;
      RECT 0.000000 899.675000 1860.340000 899.885000 ;
      RECT 0.000000 899.185000 1860.480000 899.675000 ;
      RECT 0.000000 898.975000 1860.340000 899.185000 ;
      RECT 0.000000 898.485000 1860.480000 898.975000 ;
      RECT 0.000000 898.275000 1860.340000 898.485000 ;
      RECT 0.000000 897.785000 1860.480000 898.275000 ;
      RECT 0.000000 897.575000 1860.340000 897.785000 ;
      RECT 0.000000 897.085000 1860.480000 897.575000 ;
      RECT 0.000000 896.875000 1860.340000 897.085000 ;
      RECT 0.000000 896.385000 1860.480000 896.875000 ;
      RECT 0.000000 896.175000 1860.340000 896.385000 ;
      RECT 0.000000 895.685000 1860.480000 896.175000 ;
      RECT 0.000000 895.475000 1860.340000 895.685000 ;
      RECT 0.000000 894.985000 1860.480000 895.475000 ;
      RECT 0.000000 894.775000 1860.340000 894.985000 ;
      RECT 0.000000 894.285000 1860.480000 894.775000 ;
      RECT 0.000000 894.075000 1860.340000 894.285000 ;
      RECT 0.000000 893.585000 1860.480000 894.075000 ;
      RECT 0.000000 893.375000 1860.340000 893.585000 ;
      RECT 0.000000 892.885000 1860.480000 893.375000 ;
      RECT 0.000000 892.675000 1860.340000 892.885000 ;
      RECT 0.000000 892.185000 1860.480000 892.675000 ;
      RECT 0.000000 891.975000 1860.340000 892.185000 ;
      RECT 0.000000 891.485000 1860.480000 891.975000 ;
      RECT 0.000000 891.275000 1860.340000 891.485000 ;
      RECT 0.000000 890.785000 1860.480000 891.275000 ;
      RECT 0.000000 890.575000 1860.340000 890.785000 ;
      RECT 0.000000 890.085000 1860.480000 890.575000 ;
      RECT 0.000000 889.875000 1860.340000 890.085000 ;
      RECT 0.000000 889.385000 1860.480000 889.875000 ;
      RECT 0.000000 889.175000 1860.340000 889.385000 ;
      RECT 0.000000 888.685000 1860.480000 889.175000 ;
      RECT 0.000000 888.475000 1860.340000 888.685000 ;
      RECT 0.000000 887.985000 1860.480000 888.475000 ;
      RECT 0.000000 887.775000 1860.340000 887.985000 ;
      RECT 0.000000 887.285000 1860.480000 887.775000 ;
      RECT 0.000000 887.075000 1860.340000 887.285000 ;
      RECT 0.000000 886.585000 1860.480000 887.075000 ;
      RECT 0.000000 886.375000 1860.340000 886.585000 ;
      RECT 0.000000 885.885000 1860.480000 886.375000 ;
      RECT 0.000000 885.675000 1860.340000 885.885000 ;
      RECT 0.000000 885.185000 1860.480000 885.675000 ;
      RECT 0.000000 884.975000 1860.340000 885.185000 ;
      RECT 0.000000 884.485000 1860.480000 884.975000 ;
      RECT 0.000000 884.275000 1860.340000 884.485000 ;
      RECT 0.000000 883.785000 1860.480000 884.275000 ;
      RECT 0.000000 883.575000 1860.340000 883.785000 ;
      RECT 0.000000 883.085000 1860.480000 883.575000 ;
      RECT 0.000000 882.875000 1860.340000 883.085000 ;
      RECT 0.000000 882.385000 1860.480000 882.875000 ;
      RECT 0.000000 882.175000 1860.340000 882.385000 ;
      RECT 0.000000 881.685000 1860.480000 882.175000 ;
      RECT 0.000000 881.475000 1860.340000 881.685000 ;
      RECT 0.000000 880.985000 1860.480000 881.475000 ;
      RECT 0.000000 880.775000 1860.340000 880.985000 ;
      RECT 0.000000 880.285000 1860.480000 880.775000 ;
      RECT 0.000000 880.075000 1860.340000 880.285000 ;
      RECT 0.000000 879.585000 1860.480000 880.075000 ;
      RECT 0.000000 879.375000 1860.340000 879.585000 ;
      RECT 0.000000 600.145000 1860.480000 879.375000 ;
      RECT 0.140000 599.935000 1860.480000 600.145000 ;
      RECT 0.000000 599.025000 1860.480000 599.935000 ;
      RECT 0.140000 598.815000 1860.480000 599.025000 ;
      RECT 0.000000 0.000000 1860.480000 598.815000 ;
    LAYER metal4 ;
      RECT 866.030000 1769.600000 1860.480000 1769.880000 ;
      RECT 864.630000 1769.600000 865.610000 1769.880000 ;
      RECT 863.230000 1769.600000 864.210000 1769.880000 ;
      RECT 861.830000 1769.600000 862.810000 1769.880000 ;
      RECT 860.430000 1769.600000 861.410000 1769.880000 ;
      RECT 859.030000 1769.600000 860.010000 1769.880000 ;
      RECT 857.630000 1769.600000 858.610000 1769.880000 ;
      RECT 856.230000 1769.600000 857.210000 1769.880000 ;
      RECT 854.830000 1769.600000 855.810000 1769.880000 ;
      RECT 853.430000 1769.600000 854.410000 1769.880000 ;
      RECT 852.030000 1769.600000 853.010000 1769.880000 ;
      RECT 850.630000 1769.600000 851.610000 1769.880000 ;
      RECT 849.230000 1769.600000 850.210000 1769.880000 ;
      RECT 847.830000 1769.600000 848.810000 1769.880000 ;
      RECT 846.430000 1769.600000 847.410000 1769.880000 ;
      RECT 845.030000 1769.600000 846.010000 1769.880000 ;
      RECT 843.630000 1769.600000 844.610000 1769.880000 ;
      RECT 842.230000 1769.600000 843.210000 1769.880000 ;
      RECT 840.830000 1769.600000 841.810000 1769.880000 ;
      RECT 839.430000 1769.600000 840.410000 1769.880000 ;
      RECT 838.030000 1769.600000 839.010000 1769.880000 ;
      RECT 836.630000 1769.600000 837.610000 1769.880000 ;
      RECT 0.000000 1769.600000 836.210000 1769.880000 ;
      RECT 0.000000 0.000000 1860.480000 1769.600000 ;
    LAYER metal5 ;
      RECT 0.000000 899.850000 1860.480000 1769.880000 ;
      RECT 0.000000 899.430000 1860.200000 899.850000 ;
      RECT 0.000000 898.450000 1860.480000 899.430000 ;
      RECT 0.000000 898.030000 1860.200000 898.450000 ;
      RECT 0.000000 897.050000 1860.480000 898.030000 ;
      RECT 0.000000 896.630000 1860.200000 897.050000 ;
      RECT 0.000000 895.650000 1860.480000 896.630000 ;
      RECT 0.000000 895.230000 1860.200000 895.650000 ;
      RECT 0.000000 894.250000 1860.480000 895.230000 ;
      RECT 0.000000 893.830000 1860.200000 894.250000 ;
      RECT 0.000000 892.850000 1860.480000 893.830000 ;
      RECT 0.000000 892.430000 1860.200000 892.850000 ;
      RECT 0.000000 891.450000 1860.480000 892.430000 ;
      RECT 0.000000 891.030000 1860.200000 891.450000 ;
      RECT 0.000000 890.050000 1860.480000 891.030000 ;
      RECT 0.000000 889.630000 1860.200000 890.050000 ;
      RECT 0.000000 888.650000 1860.480000 889.630000 ;
      RECT 0.000000 888.230000 1860.200000 888.650000 ;
      RECT 0.000000 887.250000 1860.480000 888.230000 ;
      RECT 0.000000 886.830000 1860.200000 887.250000 ;
      RECT 0.000000 885.850000 1860.480000 886.830000 ;
      RECT 0.000000 885.430000 1860.200000 885.850000 ;
      RECT 0.000000 884.450000 1860.480000 885.430000 ;
      RECT 0.000000 884.030000 1860.200000 884.450000 ;
      RECT 0.000000 883.050000 1860.480000 884.030000 ;
      RECT 0.000000 882.630000 1860.200000 883.050000 ;
      RECT 0.000000 881.650000 1860.480000 882.630000 ;
      RECT 0.000000 881.230000 1860.200000 881.650000 ;
      RECT 0.000000 880.250000 1860.480000 881.230000 ;
      RECT 0.000000 879.830000 1860.200000 880.250000 ;
      RECT 0.000000 878.850000 1860.480000 879.830000 ;
      RECT 0.000000 878.430000 1860.200000 878.850000 ;
      RECT 0.000000 877.450000 1860.480000 878.430000 ;
      RECT 0.000000 877.030000 1860.200000 877.450000 ;
      RECT 0.000000 876.050000 1860.480000 877.030000 ;
      RECT 0.000000 875.630000 1860.200000 876.050000 ;
      RECT 0.000000 874.650000 1860.480000 875.630000 ;
      RECT 0.000000 874.230000 1860.200000 874.650000 ;
      RECT 0.000000 873.250000 1860.480000 874.230000 ;
      RECT 0.000000 872.830000 1860.200000 873.250000 ;
      RECT 0.000000 871.850000 1860.480000 872.830000 ;
      RECT 0.000000 871.430000 1860.200000 871.850000 ;
      RECT 0.000000 870.450000 1860.480000 871.430000 ;
      RECT 0.000000 870.030000 1860.200000 870.450000 ;
      RECT 0.000000 869.050000 1860.480000 870.030000 ;
      RECT 0.000000 868.630000 1860.200000 869.050000 ;
      RECT 0.000000 867.650000 1860.480000 868.630000 ;
      RECT 0.000000 867.230000 1860.200000 867.650000 ;
      RECT 0.000000 866.250000 1860.480000 867.230000 ;
      RECT 0.000000 865.830000 1860.200000 866.250000 ;
      RECT 0.000000 864.850000 1860.480000 865.830000 ;
      RECT 0.000000 864.430000 1860.200000 864.850000 ;
      RECT 0.000000 863.450000 1860.480000 864.430000 ;
      RECT 0.000000 863.030000 1860.200000 863.450000 ;
      RECT 0.000000 862.050000 1860.480000 863.030000 ;
      RECT 0.000000 861.630000 1860.200000 862.050000 ;
      RECT 0.000000 860.650000 1860.480000 861.630000 ;
      RECT 0.000000 860.230000 1860.200000 860.650000 ;
      RECT 0.000000 859.250000 1860.480000 860.230000 ;
      RECT 0.000000 858.830000 1860.200000 859.250000 ;
      RECT 0.000000 601.090000 1860.480000 858.830000 ;
      RECT 0.280000 600.670000 1860.480000 601.090000 ;
      RECT 0.000000 599.410000 1860.480000 600.670000 ;
      RECT 0.280000 598.990000 1860.480000 599.410000 ;
      RECT 0.000000 0.000000 1860.480000 598.990000 ;
    LAYER metal6 ;
      RECT 938.270000 1769.600000 1860.480000 1769.880000 ;
      RECT 930.430000 1769.600000 937.850000 1769.880000 ;
      RECT 864.630000 1769.600000 930.010000 1769.880000 ;
      RECT 863.230000 1769.600000 864.210000 1769.880000 ;
      RECT 861.830000 1769.600000 862.810000 1769.880000 ;
      RECT 860.430000 1769.600000 861.410000 1769.880000 ;
      RECT 859.030000 1769.600000 860.010000 1769.880000 ;
      RECT 857.630000 1769.600000 858.610000 1769.880000 ;
      RECT 856.230000 1769.600000 857.210000 1769.880000 ;
      RECT 854.830000 1769.600000 855.810000 1769.880000 ;
      RECT 853.430000 1769.600000 854.410000 1769.880000 ;
      RECT 852.030000 1769.600000 853.010000 1769.880000 ;
      RECT 850.630000 1769.600000 851.610000 1769.880000 ;
      RECT 849.230000 1769.600000 850.210000 1769.880000 ;
      RECT 847.830000 1769.600000 848.810000 1769.880000 ;
      RECT 846.430000 1769.600000 847.410000 1769.880000 ;
      RECT 845.030000 1769.600000 846.010000 1769.880000 ;
      RECT 843.630000 1769.600000 844.610000 1769.880000 ;
      RECT 842.230000 1769.600000 843.210000 1769.880000 ;
      RECT 840.830000 1769.600000 841.810000 1769.880000 ;
      RECT 839.430000 1769.600000 840.410000 1769.880000 ;
      RECT 838.030000 1769.600000 839.010000 1769.880000 ;
      RECT 836.630000 1769.600000 837.610000 1769.880000 ;
      RECT 0.000000 1769.600000 836.210000 1769.880000 ;
      RECT 0.000000 0.000000 1860.480000 1769.600000 ;
    LAYER metal7 ;
      RECT 0.000000 899.960000 1860.480000 1769.880000 ;
      RECT 0.000000 898.760000 1859.680000 899.960000 ;
      RECT 0.000000 895.760000 1860.480000 898.760000 ;
      RECT 0.000000 894.560000 1859.680000 895.760000 ;
      RECT 0.000000 891.560000 1860.480000 894.560000 ;
      RECT 0.000000 890.360000 1859.680000 891.560000 ;
      RECT 0.000000 887.360000 1860.480000 890.360000 ;
      RECT 0.000000 886.160000 1859.680000 887.360000 ;
      RECT 0.000000 883.160000 1860.480000 886.160000 ;
      RECT 0.000000 881.960000 1859.680000 883.160000 ;
      RECT 0.000000 878.960000 1860.480000 881.960000 ;
      RECT 0.000000 877.760000 1859.680000 878.960000 ;
      RECT 0.000000 874.760000 1860.480000 877.760000 ;
      RECT 0.000000 873.560000 1859.680000 874.760000 ;
      RECT 0.000000 870.560000 1860.480000 873.560000 ;
      RECT 0.000000 869.360000 1859.680000 870.560000 ;
      RECT 0.000000 866.360000 1860.480000 869.360000 ;
      RECT 0.000000 865.160000 1859.680000 866.360000 ;
      RECT 0.000000 862.160000 1860.480000 865.160000 ;
      RECT 0.000000 860.960000 1859.680000 862.160000 ;
      RECT 0.000000 857.960000 1860.480000 860.960000 ;
      RECT 0.000000 856.760000 1859.680000 857.960000 ;
      RECT 0.000000 853.760000 1860.480000 856.760000 ;
      RECT 0.000000 852.560000 1859.680000 853.760000 ;
      RECT 0.000000 849.560000 1860.480000 852.560000 ;
      RECT 0.000000 848.360000 1859.680000 849.560000 ;
      RECT 0.000000 845.360000 1860.480000 848.360000 ;
      RECT 0.000000 844.160000 1859.680000 845.360000 ;
      RECT 0.000000 841.160000 1860.480000 844.160000 ;
      RECT 0.000000 839.960000 1859.680000 841.160000 ;
      RECT 0.000000 836.960000 1860.480000 839.960000 ;
      RECT 0.000000 835.760000 1859.680000 836.960000 ;
      RECT 0.000000 832.760000 1860.480000 835.760000 ;
      RECT 0.000000 831.560000 1859.680000 832.760000 ;
      RECT 0.000000 828.560000 1860.480000 831.560000 ;
      RECT 0.000000 827.360000 1859.680000 828.560000 ;
      RECT 0.000000 824.360000 1860.480000 827.360000 ;
      RECT 0.000000 823.160000 1859.680000 824.360000 ;
      RECT 0.000000 820.160000 1860.480000 823.160000 ;
      RECT 0.000000 818.960000 1859.680000 820.160000 ;
      RECT 0.000000 815.960000 1860.480000 818.960000 ;
      RECT 0.000000 814.760000 1859.680000 815.960000 ;
      RECT 0.000000 811.760000 1860.480000 814.760000 ;
      RECT 0.000000 810.560000 1859.680000 811.760000 ;
      RECT 0.000000 807.560000 1860.480000 810.560000 ;
      RECT 0.000000 806.360000 1859.680000 807.560000 ;
      RECT 0.000000 803.360000 1860.480000 806.360000 ;
      RECT 0.000000 802.160000 1859.680000 803.360000 ;
      RECT 0.000000 799.160000 1860.480000 802.160000 ;
      RECT 0.000000 797.960000 1859.680000 799.160000 ;
      RECT 0.000000 794.960000 1860.480000 797.960000 ;
      RECT 0.000000 793.760000 1859.680000 794.960000 ;
      RECT 0.000000 790.760000 1860.480000 793.760000 ;
      RECT 0.000000 789.560000 1859.680000 790.760000 ;
      RECT 0.000000 786.560000 1860.480000 789.560000 ;
      RECT 0.000000 785.360000 1859.680000 786.560000 ;
      RECT 0.000000 782.360000 1860.480000 785.360000 ;
      RECT 0.000000 781.160000 1859.680000 782.360000 ;
      RECT 0.000000 778.160000 1860.480000 781.160000 ;
      RECT 0.000000 776.960000 1859.680000 778.160000 ;
      RECT 0.000000 605.120000 1860.480000 776.960000 ;
      RECT 0.800000 603.920000 1860.480000 605.120000 ;
      RECT 0.000000 600.920000 1860.480000 603.920000 ;
      RECT 0.800000 599.720000 1860.480000 600.920000 ;
      RECT 0.000000 0.000000 1860.480000 599.720000 ;
    LAYER metal8 ;
      RECT 921.860000 1769.080000 1860.480000 1769.880000 ;
      RECT 917.660000 1769.080000 920.660000 1769.880000 ;
      RECT 913.460000 1769.080000 916.460000 1769.880000 ;
      RECT 909.260000 1769.080000 912.260000 1769.880000 ;
      RECT 905.060000 1769.080000 908.060000 1769.880000 ;
      RECT 900.860000 1769.080000 903.860000 1769.880000 ;
      RECT 896.660000 1769.080000 899.660000 1769.880000 ;
      RECT 892.460000 1769.080000 895.460000 1769.880000 ;
      RECT 888.260000 1769.080000 891.260000 1769.880000 ;
      RECT 884.060000 1769.080000 887.060000 1769.880000 ;
      RECT 879.860000 1769.080000 882.860000 1769.880000 ;
      RECT 875.660000 1769.080000 878.660000 1769.880000 ;
      RECT 871.460000 1769.080000 874.460000 1769.880000 ;
      RECT 867.260000 1769.080000 870.260000 1769.880000 ;
      RECT 863.060000 1769.080000 866.060000 1769.880000 ;
      RECT 858.860000 1769.080000 861.860000 1769.880000 ;
      RECT 854.660000 1769.080000 857.660000 1769.880000 ;
      RECT 850.460000 1769.080000 853.460000 1769.880000 ;
      RECT 846.260000 1769.080000 849.260000 1769.880000 ;
      RECT 842.060000 1769.080000 845.060000 1769.880000 ;
      RECT 837.860000 1769.080000 840.860000 1769.880000 ;
      RECT 0.000000 1769.080000 836.660000 1769.880000 ;
      RECT 0.000000 0.000000 1860.480000 1769.080000 ;
    LAYER metal9 ;
      RECT 0.000000 0.000000 1860.480000 1769.880000 ;
    LAYER metal10 ;
      RECT 0.000000 0.000000 1860.480000 1769.880000 ;
  END
END CNN_1D_Core_USE_ASIC_SRAM1

END LIBRARY
